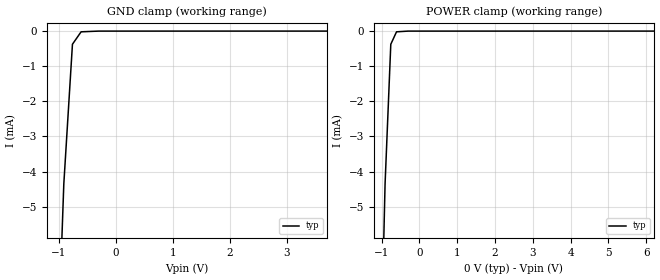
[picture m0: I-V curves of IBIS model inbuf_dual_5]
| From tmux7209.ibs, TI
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| inbuf_dual_5
[Model]   inbuf_dual_5
Model_type   Input
|   typ   min   max
C_comp   1.008417e-12   NA   NA
[Voltage Range]   0   -5   5
[Temperature Range]   27   NA   NA
[Power Clamp Reference]   0   NA   NA
[GND Clamp Reference]   0   NA   NA
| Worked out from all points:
|   GND clamp passes 1 mA (typ) near -0.78 V on its own axis
|   POWER clamp passes 1 mA (typ) near -0.78 V on its own axis
[GND Clamp]
|   Voltage   I(typ)   I(min)   I(max)
-10V      -516.8mA   NA         NA
-1.061V   -11.33mA   NA         NA
-909.1mV  -4.356mA   NA         NA
-757.6mV  -374.5uA   NA         NA
-606.1mV  -20.49uA   NA         NA
-303mV    -115.4nA   NA         NA
5V        554.8nA    NA         NA
[POWER Clamp]
|   Voltage   I(typ)   I(min)   I(max)
-5V       -231.7mA   NA         NA
-1.061V   -11.33mA   NA         NA
-909.1mV  -4.356mA   NA         NA
-757.6mV  -374.5uA   NA         NA
-606.1mV  -20.49uA   NA         NA
-303mV    -115.4nA   NA         NA
10V       555nA      NA         NA
